# Generated by FakeRAM 2.0
VERSION 5.7 ;
BUSBITCHARS "[]" ;
PROPERTYDEFINITIONS
  MACRO width INTEGER ;
  MACRO depth INTEGER ;
  MACRO banks INTEGER ;
END PROPERTYDEFINITIONS
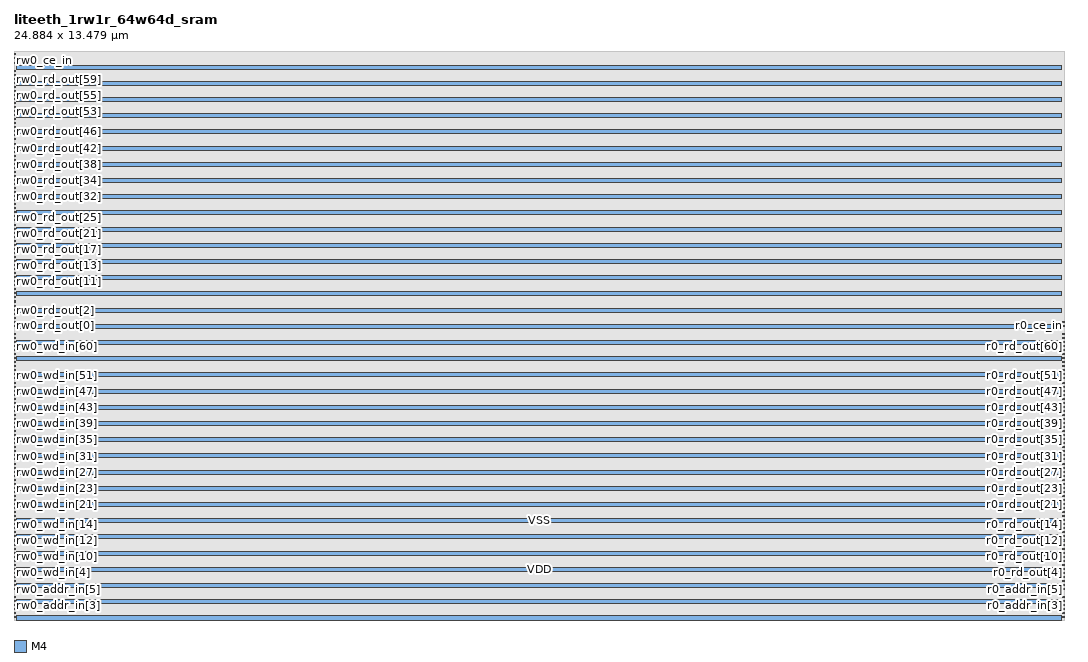
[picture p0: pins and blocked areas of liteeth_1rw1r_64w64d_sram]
MACRO liteeth_1rw1r_64w64d_sram
  PROPERTY width 64 ;
  PROPERTY depth 64 ;
  PROPERTY banks 1 ;
  FOREIGN liteeth_1rw1r_64w64d_sram 0 0 ;
  SYMMETRY X Y R90 ;
  SIZE 24.884 BY 13.479 ;
  CLASS BLOCK ;
  PIN r0_addr_in[0]
    DIRECTION INPUT ;
    USE SIGNAL ;
    SHAPE ABUTMENT ;
    PORT
      LAYER M4 ;
      RECT 24.860 0.048 24.884 0.072 ;
    END
  END r0_addr_in[0]
  PIN r0_addr_in[1]
    DIRECTION INPUT ;
    USE SIGNAL ;
    SHAPE ABUTMENT ;
    PORT
      LAYER M4 ;
      RECT 24.860 0.144 24.884 0.168 ;
    END
  END r0_addr_in[1]
  PIN r0_addr_in[2]
    DIRECTION INPUT ;
    USE SIGNAL ;
    SHAPE ABUTMENT ;
    PORT
      LAYER M4 ;
      RECT 24.860 0.240 24.884 0.264 ;
    END
  END r0_addr_in[2]
  PIN r0_addr_in[3]
    DIRECTION INPUT ;
    USE SIGNAL ;
    SHAPE ABUTMENT ;
    PORT
      LAYER M4 ;
      RECT 24.860 0.336 24.884 0.360 ;
    END
  END r0_addr_in[3]
  PIN r0_addr_in[4]
    DIRECTION INPUT ;
    USE SIGNAL ;
    SHAPE ABUTMENT ;
    PORT
      LAYER M4 ;
      RECT 24.860 0.432 24.884 0.456 ;
    END
  END r0_addr_in[4]
  PIN r0_addr_in[5]
    DIRECTION INPUT ;
    USE SIGNAL ;
    SHAPE ABUTMENT ;
    PORT
      LAYER M4 ;
      RECT 24.860 0.528 24.884 0.552 ;
    END
  END r0_addr_in[5]
  PIN r0_rd_out[0]
    DIRECTION OUTPUT ;
    USE SIGNAL ;
    SHAPE ABUTMENT ;
    PORT
      LAYER M4 ;
      RECT 24.860 0.720 24.884 0.744 ;
    END
  END r0_rd_out[0]
  PIN r0_rd_out[1]
    DIRECTION OUTPUT ;
    USE SIGNAL ;
    SHAPE ABUTMENT ;
    PORT
      LAYER M4 ;
      RECT 24.860 0.816 24.884 0.840 ;
    END
  END r0_rd_out[1]
  PIN r0_rd_out[2]
    DIRECTION OUTPUT ;
    USE SIGNAL ;
    SHAPE ABUTMENT ;
    PORT
      LAYER M4 ;
      RECT 24.860 0.912 24.884 0.936 ;
    END
  END r0_rd_out[2]
  PIN r0_rd_out[3]
    DIRECTION OUTPUT ;
    USE SIGNAL ;
    SHAPE ABUTMENT ;
    PORT
      LAYER M4 ;
      RECT 24.860 1.008 24.884 1.032 ;
    END
  END r0_rd_out[3]
  PIN r0_rd_out[4]
    DIRECTION OUTPUT ;
    USE SIGNAL ;
    SHAPE ABUTMENT ;
    PORT
      LAYER M4 ;
      RECT 24.860 1.104 24.884 1.128 ;
    END
  END r0_rd_out[4]
  PIN r0_rd_out[5]
    DIRECTION OUTPUT ;
    USE SIGNAL ;
    SHAPE ABUTMENT ;
    PORT
      LAYER M4 ;
      RECT 24.860 1.200 24.884 1.224 ;
    END
  END r0_rd_out[5]
  PIN r0_rd_out[6]
    DIRECTION OUTPUT ;
    USE SIGNAL ;
    SHAPE ABUTMENT ;
    PORT
      LAYER M4 ;
      RECT 24.860 1.296 24.884 1.320 ;
    END
  END r0_rd_out[6]
  PIN r0_rd_out[7]
    DIRECTION OUTPUT ;
    USE SIGNAL ;
    SHAPE ABUTMENT ;
    PORT
      LAYER M4 ;
      RECT 24.860 1.392 24.884 1.416 ;
    END
  END r0_rd_out[7]
  PIN r0_rd_out[8]
    DIRECTION OUTPUT ;
    USE SIGNAL ;
    SHAPE ABUTMENT ;
    PORT
      LAYER M4 ;
      RECT 24.860 1.488 24.884 1.512 ;
    END
  END r0_rd_out[8]
  PIN r0_rd_out[9]
    DIRECTION OUTPUT ;
    USE SIGNAL ;
    SHAPE ABUTMENT ;
    PORT
      LAYER M4 ;
      RECT 24.860 1.584 24.884 1.608 ;
    END
  END r0_rd_out[9]
  PIN r0_rd_out[10]
    DIRECTION OUTPUT ;
    USE SIGNAL ;
    SHAPE ABUTMENT ;
    PORT
      LAYER M4 ;
      RECT 24.860 1.680 24.884 1.704 ;
    END
  END r0_rd_out[10]
  PIN r0_rd_out[11]
    DIRECTION OUTPUT ;
    USE SIGNAL ;
    SHAPE ABUTMENT ;
    PORT
      LAYER M4 ;
      RECT 24.860 1.776 24.884 1.800 ;
    END
  END r0_rd_out[11]
  PIN r0_rd_out[12]
    DIRECTION OUTPUT ;
    USE SIGNAL ;
    SHAPE ABUTMENT ;
    PORT
      LAYER M4 ;
      RECT 24.860 1.872 24.884 1.896 ;
    END
  END r0_rd_out[12]
  PIN r0_rd_out[13]
    DIRECTION OUTPUT ;
    USE SIGNAL ;
    SHAPE ABUTMENT ;
    PORT
      LAYER M4 ;
      RECT 24.860 1.968 24.884 1.992 ;
    END
  END r0_rd_out[13]
  PIN r0_rd_out[14]
    DIRECTION OUTPUT ;
    USE SIGNAL ;
    SHAPE ABUTMENT ;
    PORT
      LAYER M4 ;
      RECT 24.860 2.064 24.884 2.088 ;
    END
  END r0_rd_out[14]
  PIN r0_rd_out[15]
    DIRECTION OUTPUT ;
    USE SIGNAL ;
    SHAPE ABUTMENT ;
    PORT
      LAYER M4 ;
      RECT 24.860 2.160 24.884 2.184 ;
    END
  END r0_rd_out[15]
  PIN r0_rd_out[16]
    DIRECTION OUTPUT ;
    USE SIGNAL ;
    SHAPE ABUTMENT ;
    PORT
      LAYER M4 ;
      RECT 24.860 2.256 24.884 2.280 ;
    END
  END r0_rd_out[16]
  PIN r0_rd_out[17]
    DIRECTION OUTPUT ;
    USE SIGNAL ;
    SHAPE ABUTMENT ;
    PORT
      LAYER M4 ;
      RECT 24.860 2.352 24.884 2.376 ;
    END
  END r0_rd_out[17]
  PIN r0_rd_out[18]
    DIRECTION OUTPUT ;
    USE SIGNAL ;
    SHAPE ABUTMENT ;
    PORT
      LAYER M4 ;
      RECT 24.860 2.448 24.884 2.472 ;
    END
  END r0_rd_out[18]
  PIN r0_rd_out[19]
    DIRECTION OUTPUT ;
    USE SIGNAL ;
    SHAPE ABUTMENT ;
    PORT
      LAYER M4 ;
      RECT 24.860 2.544 24.884 2.568 ;
    END
  END r0_rd_out[19]
  PIN r0_rd_out[20]
    DIRECTION OUTPUT ;
    USE SIGNAL ;
    SHAPE ABUTMENT ;
    PORT
      LAYER M4 ;
      RECT 24.860 2.640 24.884 2.664 ;
    END
  END r0_rd_out[20]
  PIN r0_rd_out[21]
    DIRECTION OUTPUT ;
    USE SIGNAL ;
    SHAPE ABUTMENT ;
    PORT
      LAYER M4 ;
      RECT 24.860 2.736 24.884 2.760 ;
    END
  END r0_rd_out[21]
  PIN r0_rd_out[22]
    DIRECTION OUTPUT ;
    USE SIGNAL ;
    SHAPE ABUTMENT ;
    PORT
      LAYER M4 ;
      RECT 24.860 2.832 24.884 2.856 ;
    END
  END r0_rd_out[22]
  PIN r0_rd_out[23]
    DIRECTION OUTPUT ;
    USE SIGNAL ;
    SHAPE ABUTMENT ;
    PORT
      LAYER M4 ;
      RECT 24.860 2.928 24.884 2.952 ;
    END
  END r0_rd_out[23]
  PIN r0_rd_out[24]
    DIRECTION OUTPUT ;
    USE SIGNAL ;
    SHAPE ABUTMENT ;
    PORT
      LAYER M4 ;
      RECT 24.860 3.024 24.884 3.048 ;
    END
  END r0_rd_out[24]
  PIN r0_rd_out[25]
    DIRECTION OUTPUT ;
    USE SIGNAL ;
    SHAPE ABUTMENT ;
    PORT
      LAYER M4 ;
      RECT 24.860 3.120 24.884 3.144 ;
    END
  END r0_rd_out[25]
  PIN r0_rd_out[26]
    DIRECTION OUTPUT ;
    USE SIGNAL ;
    SHAPE ABUTMENT ;
    PORT
      LAYER M4 ;
      RECT 24.860 3.216 24.884 3.240 ;
    END
  END r0_rd_out[26]
  PIN r0_rd_out[27]
    DIRECTION OUTPUT ;
    USE SIGNAL ;
    SHAPE ABUTMENT ;
    PORT
      LAYER M4 ;
      RECT 24.860 3.312 24.884 3.336 ;
    END
  END r0_rd_out[27]
  PIN r0_rd_out[28]
    DIRECTION OUTPUT ;
    USE SIGNAL ;
    SHAPE ABUTMENT ;
    PORT
      LAYER M4 ;
      RECT 24.860 3.408 24.884 3.432 ;
    END
  END r0_rd_out[28]
  PIN r0_rd_out[29]
    DIRECTION OUTPUT ;
    USE SIGNAL ;
    SHAPE ABUTMENT ;
    PORT
      LAYER M4 ;
      RECT 24.860 3.504 24.884 3.528 ;
    END
  END r0_rd_out[29]
  PIN r0_rd_out[30]
    DIRECTION OUTPUT ;
    USE SIGNAL ;
    SHAPE ABUTMENT ;
    PORT
      LAYER M4 ;
      RECT 24.860 3.600 24.884 3.624 ;
    END
  END r0_rd_out[30]
  PIN r0_rd_out[31]
    DIRECTION OUTPUT ;
    USE SIGNAL ;
    SHAPE ABUTMENT ;
    PORT
      LAYER M4 ;
      RECT 24.860 3.696 24.884 3.720 ;
    END
  END r0_rd_out[31]
  PIN r0_rd_out[32]
    DIRECTION OUTPUT ;
    USE SIGNAL ;
    SHAPE ABUTMENT ;
    PORT
      LAYER M4 ;
      RECT 24.860 3.792 24.884 3.816 ;
    END
  END r0_rd_out[32]
  PIN r0_rd_out[33]
    DIRECTION OUTPUT ;
    USE SIGNAL ;
    SHAPE ABUTMENT ;
    PORT
      LAYER M4 ;
      RECT 24.860 3.888 24.884 3.912 ;
    END
  END r0_rd_out[33]
  PIN r0_rd_out[34]
    DIRECTION OUTPUT ;
    USE SIGNAL ;
    SHAPE ABUTMENT ;
    PORT
      LAYER M4 ;
      RECT 24.860 3.984 24.884 4.008 ;
    END
  END r0_rd_out[34]
  PIN r0_rd_out[35]
    DIRECTION OUTPUT ;
    USE SIGNAL ;
    SHAPE ABUTMENT ;
    PORT
      LAYER M4 ;
      RECT 24.860 4.080 24.884 4.104 ;
    END
  END r0_rd_out[35]
  PIN r0_rd_out[36]
    DIRECTION OUTPUT ;
    USE SIGNAL ;
    SHAPE ABUTMENT ;
    PORT
      LAYER M4 ;
      RECT 24.860 4.176 24.884 4.200 ;
    END
  END r0_rd_out[36]
  PIN r0_rd_out[37]
    DIRECTION OUTPUT ;
    USE SIGNAL ;
    SHAPE ABUTMENT ;
    PORT
      LAYER M4 ;
      RECT 24.860 4.272 24.884 4.296 ;
    END
  END r0_rd_out[37]
  PIN r0_rd_out[38]
    DIRECTION OUTPUT ;
    USE SIGNAL ;
    SHAPE ABUTMENT ;
    PORT
      LAYER M4 ;
      RECT 24.860 4.368 24.884 4.392 ;
    END
  END r0_rd_out[38]
  PIN r0_rd_out[39]
    DIRECTION OUTPUT ;
    USE SIGNAL ;
    SHAPE ABUTMENT ;
    PORT
      LAYER M4 ;
      RECT 24.860 4.464 24.884 4.488 ;
    END
  END r0_rd_out[39]
  PIN r0_rd_out[40]
    DIRECTION OUTPUT ;
    USE SIGNAL ;
    SHAPE ABUTMENT ;
    PORT
      LAYER M4 ;
      RECT 24.860 4.560 24.884 4.584 ;
    END
  END r0_rd_out[40]
  PIN r0_rd_out[41]
    DIRECTION OUTPUT ;
    USE SIGNAL ;
    SHAPE ABUTMENT ;
    PORT
      LAYER M4 ;
      RECT 24.860 4.656 24.884 4.680 ;
    END
  END r0_rd_out[41]
  PIN r0_rd_out[42]
    DIRECTION OUTPUT ;
    USE SIGNAL ;
    SHAPE ABUTMENT ;
    PORT
      LAYER M4 ;
      RECT 24.860 4.752 24.884 4.776 ;
    END
  END r0_rd_out[42]
  PIN r0_rd_out[43]
    DIRECTION OUTPUT ;
    USE SIGNAL ;
    SHAPE ABUTMENT ;
    PORT
      LAYER M4 ;
      RECT 24.860 4.848 24.884 4.872 ;
    END
  END r0_rd_out[43]
  PIN r0_rd_out[44]
    DIRECTION OUTPUT ;
    USE SIGNAL ;
    SHAPE ABUTMENT ;
    PORT
      LAYER M4 ;
      RECT 24.860 4.944 24.884 4.968 ;
    END
  END r0_rd_out[44]
  PIN r0_rd_out[45]
    DIRECTION OUTPUT ;
    USE SIGNAL ;
    SHAPE ABUTMENT ;
    PORT
      LAYER M4 ;
      RECT 24.860 5.040 24.884 5.064 ;
    END
  END r0_rd_out[45]
  PIN r0_rd_out[46]
    DIRECTION OUTPUT ;
    USE SIGNAL ;
    SHAPE ABUTMENT ;
    PORT
      LAYER M4 ;
      RECT 24.860 5.136 24.884 5.160 ;
    END
  END r0_rd_out[46]
  PIN r0_rd_out[47]
    DIRECTION OUTPUT ;
    USE SIGNAL ;
    SHAPE ABUTMENT ;
    PORT
      LAYER M4 ;
      RECT 24.860 5.232 24.884 5.256 ;
    END
  END r0_rd_out[47]
  PIN r0_rd_out[48]
    DIRECTION OUTPUT ;
    USE SIGNAL ;
    SHAPE ABUTMENT ;
    PORT
      LAYER M4 ;
      RECT 24.860 5.328 24.884 5.352 ;
    END
  END r0_rd_out[48]
  PIN r0_rd_out[49]
    DIRECTION OUTPUT ;
    USE SIGNAL ;
    SHAPE ABUTMENT ;
    PORT
      LAYER M4 ;
      RECT 24.860 5.424 24.884 5.448 ;
    END
  END r0_rd_out[49]
  PIN r0_rd_out[50]
    DIRECTION OUTPUT ;
    USE SIGNAL ;
    SHAPE ABUTMENT ;
    PORT
      LAYER M4 ;
      RECT 24.860 5.520 24.884 5.544 ;
    END
  END r0_rd_out[50]
  PIN r0_rd_out[51]
    DIRECTION OUTPUT ;
    USE SIGNAL ;
    SHAPE ABUTMENT ;
    PORT
      LAYER M4 ;
      RECT 24.860 5.616 24.884 5.640 ;
    END
  END r0_rd_out[51]
  PIN r0_rd_out[52]
    DIRECTION OUTPUT ;
    USE SIGNAL ;
    SHAPE ABUTMENT ;
    PORT
      LAYER M4 ;
      RECT 24.860 5.712 24.884 5.736 ;
    END
  END r0_rd_out[52]
  PIN r0_rd_out[53]
    DIRECTION OUTPUT ;
    USE SIGNAL ;
    SHAPE ABUTMENT ;
    PORT
      LAYER M4 ;
      RECT 24.860 5.808 24.884 5.832 ;
    END
  END r0_rd_out[53]
  PIN r0_rd_out[54]
    DIRECTION OUTPUT ;
    USE SIGNAL ;
    SHAPE ABUTMENT ;
    PORT
      LAYER M4 ;
      RECT 24.860 5.904 24.884 5.928 ;
    END
  END r0_rd_out[54]
  PIN r0_rd_out[55]
    DIRECTION OUTPUT ;
    USE SIGNAL ;
    SHAPE ABUTMENT ;
    PORT
      LAYER M4 ;
      RECT 24.860 6.000 24.884 6.024 ;
    END
  END r0_rd_out[55]
  PIN r0_rd_out[56]
    DIRECTION OUTPUT ;
    USE SIGNAL ;
    SHAPE ABUTMENT ;
    PORT
      LAYER M4 ;
      RECT 24.860 6.096 24.884 6.120 ;
    END
  END r0_rd_out[56]
  PIN r0_rd_out[57]
    DIRECTION OUTPUT ;
    USE SIGNAL ;
    SHAPE ABUTMENT ;
    PORT
      LAYER M4 ;
      RECT 24.860 6.192 24.884 6.216 ;
    END
  END r0_rd_out[57]
  PIN r0_rd_out[58]
    DIRECTION OUTPUT ;
    USE SIGNAL ;
    SHAPE ABUTMENT ;
    PORT
      LAYER M4 ;
      RECT 24.860 6.288 24.884 6.312 ;
    END
  END r0_rd_out[58]
  PIN r0_rd_out[59]
    DIRECTION OUTPUT ;
    USE SIGNAL ;
    SHAPE ABUTMENT ;
    PORT
      LAYER M4 ;
      RECT 24.860 6.384 24.884 6.408 ;
    END
  END r0_rd_out[59]
  PIN r0_rd_out[60]
    DIRECTION OUTPUT ;
    USE SIGNAL ;
    SHAPE ABUTMENT ;
    PORT
      LAYER M4 ;
      RECT 24.860 6.480 24.884 6.504 ;
    END
  END r0_rd_out[60]
  PIN r0_rd_out[61]
    DIRECTION OUTPUT ;
    USE SIGNAL ;
    SHAPE ABUTMENT ;
    PORT
      LAYER M4 ;
      RECT 24.860 6.576 24.884 6.600 ;
    END
  END r0_rd_out[61]
  PIN r0_rd_out[62]
    DIRECTION OUTPUT ;
    USE SIGNAL ;
    SHAPE ABUTMENT ;
    PORT
      LAYER M4 ;
      RECT 24.860 6.672 24.884 6.696 ;
    END
  END r0_rd_out[62]
  PIN r0_rd_out[63]
    DIRECTION OUTPUT ;
    USE SIGNAL ;
    SHAPE ABUTMENT ;
    PORT
      LAYER M4 ;
      RECT 24.860 6.768 24.884 6.792 ;
    END
  END r0_rd_out[63]
  PIN r0_ce_in
    DIRECTION INPUT ;
    USE SIGNAL ;
    SHAPE ABUTMENT ;
    PORT
      LAYER M4 ;
      RECT 24.860 6.960 24.884 6.984 ;
    END
  END r0_ce_in
  PIN r0_clk
    DIRECTION INPUT ;
    USE SIGNAL ;
    SHAPE ABUTMENT ;
    PORT
      LAYER M4 ;
      RECT 24.860 7.056 24.884 7.080 ;
    END
  END r0_clk
  PIN rw0_addr_in[0]
    DIRECTION INPUT ;
    USE SIGNAL ;
    SHAPE ABUTMENT ;
    PORT
      LAYER M4 ;
      RECT 0.000 0.048 0.024 0.072 ;
    END
  END rw0_addr_in[0]
  PIN rw0_addr_in[1]
    DIRECTION INPUT ;
    USE SIGNAL ;
    SHAPE ABUTMENT ;
    PORT
      LAYER M4 ;
      RECT 0.000 0.144 0.024 0.168 ;
    END
  END rw0_addr_in[1]
  PIN rw0_addr_in[2]
    DIRECTION INPUT ;
    USE SIGNAL ;
    SHAPE ABUTMENT ;
    PORT
      LAYER M4 ;
      RECT 0.000 0.240 0.024 0.264 ;
    END
  END rw0_addr_in[2]
  PIN rw0_addr_in[3]
    DIRECTION INPUT ;
    USE SIGNAL ;
    SHAPE ABUTMENT ;
    PORT
      LAYER M4 ;
      RECT 0.000 0.336 0.024 0.360 ;
    END
  END rw0_addr_in[3]
  PIN rw0_addr_in[4]
    DIRECTION INPUT ;
    USE SIGNAL ;
    SHAPE ABUTMENT ;
    PORT
      LAYER M4 ;
      RECT 0.000 0.432 0.024 0.456 ;
    END
  END rw0_addr_in[4]
  PIN rw0_addr_in[5]
    DIRECTION INPUT ;
    USE SIGNAL ;
    SHAPE ABUTMENT ;
    PORT
      LAYER M4 ;
      RECT 0.000 0.528 0.024 0.552 ;
    END
  END rw0_addr_in[5]
  PIN rw0_wd_in[0]
    DIRECTION INPUT ;
    USE SIGNAL ;
    SHAPE ABUTMENT ;
    PORT
      LAYER M4 ;
      RECT 0.000 0.720 0.024 0.744 ;
    END
  END rw0_wd_in[0]
  PIN rw0_wd_in[1]
    DIRECTION INPUT ;
    USE SIGNAL ;
    SHAPE ABUTMENT ;
    PORT
      LAYER M4 ;
      RECT 0.000 0.816 0.024 0.840 ;
    END
  END rw0_wd_in[1]
  PIN rw0_wd_in[2]
    DIRECTION INPUT ;
    USE SIGNAL ;
    SHAPE ABUTMENT ;
    PORT
      LAYER M4 ;
      RECT 0.000 0.912 0.024 0.936 ;
    END
  END rw0_wd_in[2]
  PIN rw0_wd_in[3]
    DIRECTION INPUT ;
    USE SIGNAL ;
    SHAPE ABUTMENT ;
    PORT
      LAYER M4 ;
      RECT 0.000 1.008 0.024 1.032 ;
    END
  END rw0_wd_in[3]
  PIN rw0_wd_in[4]
    DIRECTION INPUT ;
    USE SIGNAL ;
    SHAPE ABUTMENT ;
    PORT
      LAYER M4 ;
      RECT 0.000 1.104 0.024 1.128 ;
    END
  END rw0_wd_in[4]
  PIN rw0_wd_in[5]
    DIRECTION INPUT ;
    USE SIGNAL ;
    SHAPE ABUTMENT ;
    PORT
      LAYER M4 ;
      RECT 0.000 1.200 0.024 1.224 ;
    END
  END rw0_wd_in[5]
  PIN rw0_wd_in[6]
    DIRECTION INPUT ;
    USE SIGNAL ;
    SHAPE ABUTMENT ;
    PORT
      LAYER M4 ;
      RECT 0.000 1.296 0.024 1.320 ;
    END
  END rw0_wd_in[6]
  PIN rw0_wd_in[7]
    DIRECTION INPUT ;
    USE SIGNAL ;
    SHAPE ABUTMENT ;
    PORT
      LAYER M4 ;
      RECT 0.000 1.392 0.024 1.416 ;
    END
  END rw0_wd_in[7]
  PIN rw0_wd_in[8]
    DIRECTION INPUT ;
    USE SIGNAL ;
    SHAPE ABUTMENT ;
    PORT
      LAYER M4 ;
      RECT 0.000 1.488 0.024 1.512 ;
    END
  END rw0_wd_in[8]
  PIN rw0_wd_in[9]
    DIRECTION INPUT ;
    USE SIGNAL ;
    SHAPE ABUTMENT ;
    PORT
      LAYER M4 ;
      RECT 0.000 1.584 0.024 1.608 ;
    END
  END rw0_wd_in[9]
  PIN rw0_wd_in[10]
    DIRECTION INPUT ;
    USE SIGNAL ;
    SHAPE ABUTMENT ;
    PORT
      LAYER M4 ;
      RECT 0.000 1.680 0.024 1.704 ;
    END
  END rw0_wd_in[10]
  PIN rw0_wd_in[11]
    DIRECTION INPUT ;
    USE SIGNAL ;
    SHAPE ABUTMENT ;
    PORT
      LAYER M4 ;
      RECT 0.000 1.776 0.024 1.800 ;
    END
  END rw0_wd_in[11]
  PIN rw0_wd_in[12]
    DIRECTION INPUT ;
    USE SIGNAL ;
    SHAPE ABUTMENT ;
    PORT
      LAYER M4 ;
      RECT 0.000 1.872 0.024 1.896 ;
    END
  END rw0_wd_in[12]
  PIN rw0_wd_in[13]
    DIRECTION INPUT ;
    USE SIGNAL ;
    SHAPE ABUTMENT ;
    PORT
      LAYER M4 ;
      RECT 0.000 1.968 0.024 1.992 ;
    END
  END rw0_wd_in[13]
  PIN rw0_wd_in[14]
    DIRECTION INPUT ;
    USE SIGNAL ;
    SHAPE ABUTMENT ;
    PORT
      LAYER M4 ;
      RECT 0.000 2.064 0.024 2.088 ;
    END
  END rw0_wd_in[14]
  PIN rw0_wd_in[15]
    DIRECTION INPUT ;
    USE SIGNAL ;
    SHAPE ABUTMENT ;
    PORT
      LAYER M4 ;
      RECT 0.000 2.160 0.024 2.184 ;
    END
  END rw0_wd_in[15]
  PIN rw0_wd_in[16]
    DIRECTION INPUT ;
    USE SIGNAL ;
    SHAPE ABUTMENT ;
    PORT
      LAYER M4 ;
      RECT 0.000 2.256 0.024 2.280 ;
    END
  END rw0_wd_in[16]
  PIN rw0_wd_in[17]
    DIRECTION INPUT ;
    USE SIGNAL ;
    SHAPE ABUTMENT ;
    PORT
      LAYER M4 ;
      RECT 0.000 2.352 0.024 2.376 ;
    END
  END rw0_wd_in[17]
  PIN rw0_wd_in[18]
    DIRECTION INPUT ;
    USE SIGNAL ;
    SHAPE ABUTMENT ;
    PORT
      LAYER M4 ;
      RECT 0.000 2.448 0.024 2.472 ;
    END
  END rw0_wd_in[18]
  PIN rw0_wd_in[19]
    DIRECTION INPUT ;
    USE SIGNAL ;
    SHAPE ABUTMENT ;
    PORT
      LAYER M4 ;
      RECT 0.000 2.544 0.024 2.568 ;
    END
  END rw0_wd_in[19]
  PIN rw0_wd_in[20]
    DIRECTION INPUT ;
    USE SIGNAL ;
    SHAPE ABUTMENT ;
    PORT
      LAYER M4 ;
      RECT 0.000 2.640 0.024 2.664 ;
    END
  END rw0_wd_in[20]
  PIN rw0_wd_in[21]
    DIRECTION INPUT ;
    USE SIGNAL ;
    SHAPE ABUTMENT ;
    PORT
      LAYER M4 ;
      RECT 0.000 2.736 0.024 2.760 ;
    END
  END rw0_wd_in[21]
  PIN rw0_wd_in[22]
    DIRECTION INPUT ;
    USE SIGNAL ;
    SHAPE ABUTMENT ;
    PORT
      LAYER M4 ;
      RECT 0.000 2.832 0.024 2.856 ;
    END
  END rw0_wd_in[22]
  PIN rw0_wd_in[23]
    DIRECTION INPUT ;
    USE SIGNAL ;
    SHAPE ABUTMENT ;
    PORT
      LAYER M4 ;
      RECT 0.000 2.928 0.024 2.952 ;
    END
  END rw0_wd_in[23]
  PIN rw0_wd_in[24]
    DIRECTION INPUT ;
    USE SIGNAL ;
    SHAPE ABUTMENT ;
    PORT
      LAYER M4 ;
      RECT 0.000 3.024 0.024 3.048 ;
    END
  END rw0_wd_in[24]
  PIN rw0_wd_in[25]
    DIRECTION INPUT ;
    USE SIGNAL ;
    SHAPE ABUTMENT ;
    PORT
      LAYER M4 ;
      RECT 0.000 3.120 0.024 3.144 ;
    END
  END rw0_wd_in[25]
  PIN rw0_wd_in[26]
    DIRECTION INPUT ;
    USE SIGNAL ;
    SHAPE ABUTMENT ;
    PORT
      LAYER M4 ;
      RECT 0.000 3.216 0.024 3.240 ;
    END
  END rw0_wd_in[26]
  PIN rw0_wd_in[27]
    DIRECTION INPUT ;
    USE SIGNAL ;
    SHAPE ABUTMENT ;
    PORT
      LAYER M4 ;
      RECT 0.000 3.312 0.024 3.336 ;
    END
  END rw0_wd_in[27]
  PIN rw0_wd_in[28]
    DIRECTION INPUT ;
    USE SIGNAL ;
    SHAPE ABUTMENT ;
    PORT
      LAYER M4 ;
      RECT 0.000 3.408 0.024 3.432 ;
    END
  END rw0_wd_in[28]
  PIN rw0_wd_in[29]
    DIRECTION INPUT ;
    USE SIGNAL ;
    SHAPE ABUTMENT ;
    PORT
      LAYER M4 ;
      RECT 0.000 3.504 0.024 3.528 ;
    END
  END rw0_wd_in[29]
  PIN rw0_wd_in[30]
    DIRECTION INPUT ;
    USE SIGNAL ;
    SHAPE ABUTMENT ;
    PORT
      LAYER M4 ;
      RECT 0.000 3.600 0.024 3.624 ;
    END
  END rw0_wd_in[30]
  PIN rw0_wd_in[31]
    DIRECTION INPUT ;
    USE SIGNAL ;
    SHAPE ABUTMENT ;
    PORT
      LAYER M4 ;
      RECT 0.000 3.696 0.024 3.720 ;
    END
  END rw0_wd_in[31]
  PIN rw0_wd_in[32]
    DIRECTION INPUT ;
    USE SIGNAL ;
    SHAPE ABUTMENT ;
    PORT
      LAYER M4 ;
      RECT 0.000 3.792 0.024 3.816 ;
    END
  END rw0_wd_in[32]
  PIN rw0_wd_in[33]
    DIRECTION INPUT ;
    USE SIGNAL ;
    SHAPE ABUTMENT ;
    PORT
      LAYER M4 ;
      RECT 0.000 3.888 0.024 3.912 ;
    END
  END rw0_wd_in[33]
  PIN rw0_wd_in[34]
    DIRECTION INPUT ;
    USE SIGNAL ;
    SHAPE ABUTMENT ;
    PORT
      LAYER M4 ;
      RECT 0.000 3.984 0.024 4.008 ;
    END
  END rw0_wd_in[34]
  PIN rw0_wd_in[35]
    DIRECTION INPUT ;
    USE SIGNAL ;
    SHAPE ABUTMENT ;
    PORT
      LAYER M4 ;
      RECT 0.000 4.080 0.024 4.104 ;
    END
  END rw0_wd_in[35]
  PIN rw0_wd_in[36]
    DIRECTION INPUT ;
    USE SIGNAL ;
    SHAPE ABUTMENT ;
    PORT
      LAYER M4 ;
      RECT 0.000 4.176 0.024 4.200 ;
    END
  END rw0_wd_in[36]
  PIN rw0_wd_in[37]
    DIRECTION INPUT ;
    USE SIGNAL ;
    SHAPE ABUTMENT ;
    PORT
      LAYER M4 ;
      RECT 0.000 4.272 0.024 4.296 ;
    END
  END rw0_wd_in[37]
  PIN rw0_wd_in[38]
    DIRECTION INPUT ;
    USE SIGNAL ;
    SHAPE ABUTMENT ;
    PORT
      LAYER M4 ;
      RECT 0.000 4.368 0.024 4.392 ;
    END
  END rw0_wd_in[38]
  PIN rw0_wd_in[39]
    DIRECTION INPUT ;
    USE SIGNAL ;
    SHAPE ABUTMENT ;
    PORT
      LAYER M4 ;
      RECT 0.000 4.464 0.024 4.488 ;
    END
  END rw0_wd_in[39]
  PIN rw0_wd_in[40]
    DIRECTION INPUT ;
    USE SIGNAL ;
    SHAPE ABUTMENT ;
    PORT
      LAYER M4 ;
      RECT 0.000 4.560 0.024 4.584 ;
    END
  END rw0_wd_in[40]
  PIN rw0_wd_in[41]
    DIRECTION INPUT ;
    USE SIGNAL ;
    SHAPE ABUTMENT ;
    PORT
      LAYER M4 ;
      RECT 0.000 4.656 0.024 4.680 ;
    END
  END rw0_wd_in[41]
  PIN rw0_wd_in[42]
    DIRECTION INPUT ;
    USE SIGNAL ;
    SHAPE ABUTMENT ;
    PORT
      LAYER M4 ;
      RECT 0.000 4.752 0.024 4.776 ;
    END
  END rw0_wd_in[42]
  PIN rw0_wd_in[43]
    DIRECTION INPUT ;
    USE SIGNAL ;
    SHAPE ABUTMENT ;
    PORT
      LAYER M4 ;
      RECT 0.000 4.848 0.024 4.872 ;
    END
  END rw0_wd_in[43]
  PIN rw0_wd_in[44]
    DIRECTION INPUT ;
    USE SIGNAL ;
    SHAPE ABUTMENT ;
    PORT
      LAYER M4 ;
      RECT 0.000 4.944 0.024 4.968 ;
    END
  END rw0_wd_in[44]
  PIN rw0_wd_in[45]
    DIRECTION INPUT ;
    USE SIGNAL ;
    SHAPE ABUTMENT ;
    PORT
      LAYER M4 ;
      RECT 0.000 5.040 0.024 5.064 ;
    END
  END rw0_wd_in[45]
  PIN rw0_wd_in[46]
    DIRECTION INPUT ;
    USE SIGNAL ;
    SHAPE ABUTMENT ;
    PORT
      LAYER M4 ;
      RECT 0.000 5.136 0.024 5.160 ;
    END
  END rw0_wd_in[46]
  PIN rw0_wd_in[47]
    DIRECTION INPUT ;
    USE SIGNAL ;
    SHAPE ABUTMENT ;
    PORT
      LAYER M4 ;
      RECT 0.000 5.232 0.024 5.256 ;
    END
  END rw0_wd_in[47]
  PIN rw0_wd_in[48]
    DIRECTION INPUT ;
    USE SIGNAL ;
    SHAPE ABUTMENT ;
    PORT
      LAYER M4 ;
      RECT 0.000 5.328 0.024 5.352 ;
    END
  END rw0_wd_in[48]
  PIN rw0_wd_in[49]
    DIRECTION INPUT ;
    USE SIGNAL ;
    SHAPE ABUTMENT ;
    PORT
      LAYER M4 ;
      RECT 0.000 5.424 0.024 5.448 ;
    END
  END rw0_wd_in[49]
  PIN rw0_wd_in[50]
    DIRECTION INPUT ;
    USE SIGNAL ;
    SHAPE ABUTMENT ;
    PORT
      LAYER M4 ;
      RECT 0.000 5.520 0.024 5.544 ;
    END
  END rw0_wd_in[50]
  PIN rw0_wd_in[51]
    DIRECTION INPUT ;
    USE SIGNAL ;
    SHAPE ABUTMENT ;
    PORT
      LAYER M4 ;
      RECT 0.000 5.616 0.024 5.640 ;
    END
  END rw0_wd_in[51]
  PIN rw0_wd_in[52]
    DIRECTION INPUT ;
    USE SIGNAL ;
    SHAPE ABUTMENT ;
    PORT
      LAYER M4 ;
      RECT 0.000 5.712 0.024 5.736 ;
    END
  END rw0_wd_in[52]
  PIN rw0_wd_in[53]
    DIRECTION INPUT ;
    USE SIGNAL ;
    SHAPE ABUTMENT ;
    PORT
      LAYER M4 ;
      RECT 0.000 5.808 0.024 5.832 ;
    END
  END rw0_wd_in[53]
  PIN rw0_wd_in[54]
    DIRECTION INPUT ;
    USE SIGNAL ;
    SHAPE ABUTMENT ;
    PORT
      LAYER M4 ;
      RECT 0.000 5.904 0.024 5.928 ;
    END
  END rw0_wd_in[54]
  PIN rw0_wd_in[55]
    DIRECTION INPUT ;
    USE SIGNAL ;
    SHAPE ABUTMENT ;
    PORT
      LAYER M4 ;
      RECT 0.000 6.000 0.024 6.024 ;
    END
  END rw0_wd_in[55]
  PIN rw0_wd_in[56]
    DIRECTION INPUT ;
    USE SIGNAL ;
    SHAPE ABUTMENT ;
    PORT
      LAYER M4 ;
      RECT 0.000 6.096 0.024 6.120 ;
    END
  END rw0_wd_in[56]
  PIN rw0_wd_in[57]
    DIRECTION INPUT ;
    USE SIGNAL ;
    SHAPE ABUTMENT ;
    PORT
      LAYER M4 ;
      RECT 0.000 6.192 0.024 6.216 ;
    END
  END rw0_wd_in[57]
  PIN rw0_wd_in[58]
    DIRECTION INPUT ;
    USE SIGNAL ;
    SHAPE ABUTMENT ;
    PORT
      LAYER M4 ;
      RECT 0.000 6.288 0.024 6.312 ;
    END
  END rw0_wd_in[58]
  PIN rw0_wd_in[59]
    DIRECTION INPUT ;
    USE SIGNAL ;
    SHAPE ABUTMENT ;
    PORT
      LAYER M4 ;
      RECT 0.000 6.384 0.024 6.408 ;
    END
  END rw0_wd_in[59]
  PIN rw0_wd_in[60]
    DIRECTION INPUT ;
    USE SIGNAL ;
    SHAPE ABUTMENT ;
    PORT
      LAYER M4 ;
      RECT 0.000 6.480 0.024 6.504 ;
    END
  END rw0_wd_in[60]
  PIN rw0_wd_in[61]
    DIRECTION INPUT ;
    USE SIGNAL ;
    SHAPE ABUTMENT ;
    PORT
      LAYER M4 ;
      RECT 0.000 6.576 0.024 6.600 ;
    END
  END rw0_wd_in[61]
  PIN rw0_wd_in[62]
    DIRECTION INPUT ;
    USE SIGNAL ;
    SHAPE ABUTMENT ;
    PORT
      LAYER M4 ;
      RECT 0.000 6.672 0.024 6.696 ;
    END
  END rw0_wd_in[62]
  PIN rw0_wd_in[63]
    DIRECTION INPUT ;
    USE SIGNAL ;
    SHAPE ABUTMENT ;
    PORT
      LAYER M4 ;
      RECT 0.000 6.768 0.024 6.792 ;
    END
  END rw0_wd_in[63]
  PIN rw0_rd_out[0]
    DIRECTION OUTPUT ;
    USE SIGNAL ;
    SHAPE ABUTMENT ;
    PORT
      LAYER M4 ;
      RECT 0.000 6.960 0.024 6.984 ;
    END
  END rw0_rd_out[0]
  PIN rw0_rd_out[1]
    DIRECTION OUTPUT ;
    USE SIGNAL ;
    SHAPE ABUTMENT ;
    PORT
      LAYER M4 ;
      RECT 0.000 7.056 0.024 7.080 ;
    END
  END rw0_rd_out[1]
  PIN rw0_rd_out[2]
    DIRECTION OUTPUT ;
    USE SIGNAL ;
    SHAPE ABUTMENT ;
    PORT
      LAYER M4 ;
      RECT 0.000 7.152 0.024 7.176 ;
    END
  END rw0_rd_out[2]
  PIN rw0_rd_out[3]
    DIRECTION OUTPUT ;
    USE SIGNAL ;
    SHAPE ABUTMENT ;
    PORT
      LAYER M4 ;
      RECT 0.000 7.248 0.024 7.272 ;
    END
  END rw0_rd_out[3]
  PIN rw0_rd_out[4]
    DIRECTION OUTPUT ;
    USE SIGNAL ;
    SHAPE ABUTMENT ;
    PORT
      LAYER M4 ;
      RECT 0.000 7.344 0.024 7.368 ;
    END
  END rw0_rd_out[4]
  PIN rw0_rd_out[5]
    DIRECTION OUTPUT ;
    USE SIGNAL ;
    SHAPE ABUTMENT ;
    PORT
      LAYER M4 ;
      RECT 0.000 7.440 0.024 7.464 ;
    END
  END rw0_rd_out[5]
  PIN rw0_rd_out[6]
    DIRECTION OUTPUT ;
    USE SIGNAL ;
    SHAPE ABUTMENT ;
    PORT
      LAYER M4 ;
      RECT 0.000 7.536 0.024 7.560 ;
    END
  END rw0_rd_out[6]
  PIN rw0_rd_out[7]
    DIRECTION OUTPUT ;
    USE SIGNAL ;
    SHAPE ABUTMENT ;
    PORT
      LAYER M4 ;
      RECT 0.000 7.632 0.024 7.656 ;
    END
  END rw0_rd_out[7]
  PIN rw0_rd_out[8]
    DIRECTION OUTPUT ;
    USE SIGNAL ;
    SHAPE ABUTMENT ;
    PORT
      LAYER M4 ;
      RECT 0.000 7.728 0.024 7.752 ;
    END
  END rw0_rd_out[8]
  PIN rw0_rd_out[9]
    DIRECTION OUTPUT ;
    USE SIGNAL ;
    SHAPE ABUTMENT ;
    PORT
      LAYER M4 ;
      RECT 0.000 7.824 0.024 7.848 ;
    END
  END rw0_rd_out[9]
  PIN rw0_rd_out[10]
    DIRECTION OUTPUT ;
    USE SIGNAL ;
    SHAPE ABUTMENT ;
    PORT
      LAYER M4 ;
      RECT 0.000 7.920 0.024 7.944 ;
    END
  END rw0_rd_out[10]
  PIN rw0_rd_out[11]
    DIRECTION OUTPUT ;
    USE SIGNAL ;
    SHAPE ABUTMENT ;
    PORT
      LAYER M4 ;
      RECT 0.000 8.016 0.024 8.040 ;
    END
  END rw0_rd_out[11]
  PIN rw0_rd_out[12]
    DIRECTION OUTPUT ;
    USE SIGNAL ;
    SHAPE ABUTMENT ;
    PORT
      LAYER M4 ;
      RECT 0.000 8.112 0.024 8.136 ;
    END
  END rw0_rd_out[12]
  PIN rw0_rd_out[13]
    DIRECTION OUTPUT ;
    USE SIGNAL ;
    SHAPE ABUTMENT ;
    PORT
      LAYER M4 ;
      RECT 0.000 8.208 0.024 8.232 ;
    END
  END rw0_rd_out[13]
  PIN rw0_rd_out[14]
    DIRECTION OUTPUT ;
    USE SIGNAL ;
    SHAPE ABUTMENT ;
    PORT
      LAYER M4 ;
      RECT 0.000 8.304 0.024 8.328 ;
    END
  END rw0_rd_out[14]
  PIN rw0_rd_out[15]
    DIRECTION OUTPUT ;
    USE SIGNAL ;
    SHAPE ABUTMENT ;
    PORT
      LAYER M4 ;
      RECT 0.000 8.400 0.024 8.424 ;
    END
  END rw0_rd_out[15]
  PIN rw0_rd_out[16]
    DIRECTION OUTPUT ;
    USE SIGNAL ;
    SHAPE ABUTMENT ;
    PORT
      LAYER M4 ;
      RECT 0.000 8.496 0.024 8.520 ;
    END
  END rw0_rd_out[16]
  PIN rw0_rd_out[17]
    DIRECTION OUTPUT ;
    USE SIGNAL ;
    SHAPE ABUTMENT ;
    PORT
      LAYER M4 ;
      RECT 0.000 8.592 0.024 8.616 ;
    END
  END rw0_rd_out[17]
  PIN rw0_rd_out[18]
    DIRECTION OUTPUT ;
    USE SIGNAL ;
    SHAPE ABUTMENT ;
    PORT
      LAYER M4 ;
      RECT 0.000 8.688 0.024 8.712 ;
    END
  END rw0_rd_out[18]
  PIN rw0_rd_out[19]
    DIRECTION OUTPUT ;
    USE SIGNAL ;
    SHAPE ABUTMENT ;
    PORT
      LAYER M4 ;
      RECT 0.000 8.784 0.024 8.808 ;
    END
  END rw0_rd_out[19]
  PIN rw0_rd_out[20]
    DIRECTION OUTPUT ;
    USE SIGNAL ;
    SHAPE ABUTMENT ;
    PORT
      LAYER M4 ;
      RECT 0.000 8.880 0.024 8.904 ;
    END
  END rw0_rd_out[20]
  PIN rw0_rd_out[21]
    DIRECTION OUTPUT ;
    USE SIGNAL ;
    SHAPE ABUTMENT ;
    PORT
      LAYER M4 ;
      RECT 0.000 8.976 0.024 9.000 ;
    END
  END rw0_rd_out[21]
  PIN rw0_rd_out[22]
    DIRECTION OUTPUT ;
    USE SIGNAL ;
    SHAPE ABUTMENT ;
    PORT
      LAYER M4 ;
      RECT 0.000 9.072 0.024 9.096 ;
    END
  END rw0_rd_out[22]
  PIN rw0_rd_out[23]
    DIRECTION OUTPUT ;
    USE SIGNAL ;
    SHAPE ABUTMENT ;
    PORT
      LAYER M4 ;
      RECT 0.000 9.168 0.024 9.192 ;
    END
  END rw0_rd_out[23]
  PIN rw0_rd_out[24]
    DIRECTION OUTPUT ;
    USE SIGNAL ;
    SHAPE ABUTMENT ;
    PORT
      LAYER M4 ;
      RECT 0.000 9.264 0.024 9.288 ;
    END
  END rw0_rd_out[24]
  PIN rw0_rd_out[25]
    DIRECTION OUTPUT ;
    USE SIGNAL ;
    SHAPE ABUTMENT ;
    PORT
      LAYER M4 ;
      RECT 0.000 9.360 0.024 9.384 ;
    END
  END rw0_rd_out[25]
  PIN rw0_rd_out[26]
    DIRECTION OUTPUT ;
    USE SIGNAL ;
    SHAPE ABUTMENT ;
    PORT
      LAYER M4 ;
      RECT 0.000 9.456 0.024 9.480 ;
    END
  END rw0_rd_out[26]
  PIN rw0_rd_out[27]
    DIRECTION OUTPUT ;
    USE SIGNAL ;
    SHAPE ABUTMENT ;
    PORT
      LAYER M4 ;
      RECT 0.000 9.552 0.024 9.576 ;
    END
  END rw0_rd_out[27]
  PIN rw0_rd_out[28]
    DIRECTION OUTPUT ;
    USE SIGNAL ;
    SHAPE ABUTMENT ;
    PORT
      LAYER M4 ;
      RECT 0.000 9.648 0.024 9.672 ;
    END
  END rw0_rd_out[28]
  PIN rw0_rd_out[29]
    DIRECTION OUTPUT ;
    USE SIGNAL ;
    SHAPE ABUTMENT ;
    PORT
      LAYER M4 ;
      RECT 0.000 9.744 0.024 9.768 ;
    END
  END rw0_rd_out[29]
  PIN rw0_rd_out[30]
    DIRECTION OUTPUT ;
    USE SIGNAL ;
    SHAPE ABUTMENT ;
    PORT
      LAYER M4 ;
      RECT 0.000 9.840 0.024 9.864 ;
    END
  END rw0_rd_out[30]
  PIN rw0_rd_out[31]
    DIRECTION OUTPUT ;
    USE SIGNAL ;
    SHAPE ABUTMENT ;
    PORT
      LAYER M4 ;
      RECT 0.000 9.936 0.024 9.960 ;
    END
  END rw0_rd_out[31]
  PIN rw0_rd_out[32]
    DIRECTION OUTPUT ;
    USE SIGNAL ;
    SHAPE ABUTMENT ;
    PORT
      LAYER M4 ;
      RECT 0.000 10.032 0.024 10.056 ;
    END
  END rw0_rd_out[32]
  PIN rw0_rd_out[33]
    DIRECTION OUTPUT ;
    USE SIGNAL ;
    SHAPE ABUTMENT ;
    PORT
      LAYER M4 ;
      RECT 0.000 10.128 0.024 10.152 ;
    END
  END rw0_rd_out[33]
  PIN rw0_rd_out[34]
    DIRECTION OUTPUT ;
    USE SIGNAL ;
    SHAPE ABUTMENT ;
    PORT
      LAYER M4 ;
      RECT 0.000 10.224 0.024 10.248 ;
    END
  END rw0_rd_out[34]
  PIN rw0_rd_out[35]
    DIRECTION OUTPUT ;
    USE SIGNAL ;
    SHAPE ABUTMENT ;
    PORT
      LAYER M4 ;
      RECT 0.000 10.320 0.024 10.344 ;
    END
  END rw0_rd_out[35]
  PIN rw0_rd_out[36]
    DIRECTION OUTPUT ;
    USE SIGNAL ;
    SHAPE ABUTMENT ;
    PORT
      LAYER M4 ;
      RECT 0.000 10.416 0.024 10.440 ;
    END
  END rw0_rd_out[36]
  PIN rw0_rd_out[37]
    DIRECTION OUTPUT ;
    USE SIGNAL ;
    SHAPE ABUTMENT ;
    PORT
      LAYER M4 ;
      RECT 0.000 10.512 0.024 10.536 ;
    END
  END rw0_rd_out[37]
  PIN rw0_rd_out[38]
    DIRECTION OUTPUT ;
    USE SIGNAL ;
    SHAPE ABUTMENT ;
    PORT
      LAYER M4 ;
      RECT 0.000 10.608 0.024 10.632 ;
    END
  END rw0_rd_out[38]
  PIN rw0_rd_out[39]
    DIRECTION OUTPUT ;
    USE SIGNAL ;
    SHAPE ABUTMENT ;
    PORT
      LAYER M4 ;
      RECT 0.000 10.704 0.024 10.728 ;
    END
  END rw0_rd_out[39]
  PIN rw0_rd_out[40]
    DIRECTION OUTPUT ;
    USE SIGNAL ;
    SHAPE ABUTMENT ;
    PORT
      LAYER M4 ;
      RECT 0.000 10.800 0.024 10.824 ;
    END
  END rw0_rd_out[40]
  PIN rw0_rd_out[41]
    DIRECTION OUTPUT ;
    USE SIGNAL ;
    SHAPE ABUTMENT ;
    PORT
      LAYER M4 ;
      RECT 0.000 10.896 0.024 10.920 ;
    END
  END rw0_rd_out[41]
  PIN rw0_rd_out[42]
    DIRECTION OUTPUT ;
    USE SIGNAL ;
    SHAPE ABUTMENT ;
    PORT
      LAYER M4 ;
      RECT 0.000 10.992 0.024 11.016 ;
    END
  END rw0_rd_out[42]
  PIN rw0_rd_out[43]
    DIRECTION OUTPUT ;
    USE SIGNAL ;
    SHAPE ABUTMENT ;
    PORT
      LAYER M4 ;
      RECT 0.000 11.088 0.024 11.112 ;
    END
  END rw0_rd_out[43]
  PIN rw0_rd_out[44]
    DIRECTION OUTPUT ;
    USE SIGNAL ;
    SHAPE ABUTMENT ;
    PORT
      LAYER M4 ;
      RECT 0.000 11.184 0.024 11.208 ;
    END
  END rw0_rd_out[44]
  PIN rw0_rd_out[45]
    DIRECTION OUTPUT ;
    USE SIGNAL ;
    SHAPE ABUTMENT ;
    PORT
      LAYER M4 ;
      RECT 0.000 11.280 0.024 11.304 ;
    END
  END rw0_rd_out[45]
  PIN rw0_rd_out[46]
    DIRECTION OUTPUT ;
    USE SIGNAL ;
    SHAPE ABUTMENT ;
    PORT
      LAYER M4 ;
      RECT 0.000 11.376 0.024 11.400 ;
    END
  END rw0_rd_out[46]
  PIN rw0_rd_out[47]
    DIRECTION OUTPUT ;
    USE SIGNAL ;
    SHAPE ABUTMENT ;
    PORT
      LAYER M4 ;
      RECT 0.000 11.472 0.024 11.496 ;
    END
  END rw0_rd_out[47]
  PIN rw0_rd_out[48]
    DIRECTION OUTPUT ;
    USE SIGNAL ;
    SHAPE ABUTMENT ;
    PORT
      LAYER M4 ;
      RECT 0.000 11.568 0.024 11.592 ;
    END
  END rw0_rd_out[48]
  PIN rw0_rd_out[49]
    DIRECTION OUTPUT ;
    USE SIGNAL ;
    SHAPE ABUTMENT ;
    PORT
      LAYER M4 ;
      RECT 0.000 11.664 0.024 11.688 ;
    END
  END rw0_rd_out[49]
  PIN rw0_rd_out[50]
    DIRECTION OUTPUT ;
    USE SIGNAL ;
    SHAPE ABUTMENT ;
    PORT
      LAYER M4 ;
      RECT 0.000 11.760 0.024 11.784 ;
    END
  END rw0_rd_out[50]
  PIN rw0_rd_out[51]
    DIRECTION OUTPUT ;
    USE SIGNAL ;
    SHAPE ABUTMENT ;
    PORT
      LAYER M4 ;
      RECT 0.000 11.856 0.024 11.880 ;
    END
  END rw0_rd_out[51]
  PIN rw0_rd_out[52]
    DIRECTION OUTPUT ;
    USE SIGNAL ;
    SHAPE ABUTMENT ;
    PORT
      LAYER M4 ;
      RECT 0.000 11.952 0.024 11.976 ;
    END
  END rw0_rd_out[52]
  PIN rw0_rd_out[53]
    DIRECTION OUTPUT ;
    USE SIGNAL ;
    SHAPE ABUTMENT ;
    PORT
      LAYER M4 ;
      RECT 0.000 12.048 0.024 12.072 ;
    END
  END rw0_rd_out[53]
  PIN rw0_rd_out[54]
    DIRECTION OUTPUT ;
    USE SIGNAL ;
    SHAPE ABUTMENT ;
    PORT
      LAYER M4 ;
      RECT 0.000 12.144 0.024 12.168 ;
    END
  END rw0_rd_out[54]
  PIN rw0_rd_out[55]
    DIRECTION OUTPUT ;
    USE SIGNAL ;
    SHAPE ABUTMENT ;
    PORT
      LAYER M4 ;
      RECT 0.000 12.240 0.024 12.264 ;
    END
  END rw0_rd_out[55]
  PIN rw0_rd_out[56]
    DIRECTION OUTPUT ;
    USE SIGNAL ;
    SHAPE ABUTMENT ;
    PORT
      LAYER M4 ;
      RECT 0.000 12.336 0.024 12.360 ;
    END
  END rw0_rd_out[56]
  PIN rw0_rd_out[57]
    DIRECTION OUTPUT ;
    USE SIGNAL ;
    SHAPE ABUTMENT ;
    PORT
      LAYER M4 ;
      RECT 0.000 12.432 0.024 12.456 ;
    END
  END rw0_rd_out[57]
  PIN rw0_rd_out[58]
    DIRECTION OUTPUT ;
    USE SIGNAL ;
    SHAPE ABUTMENT ;
    PORT
      LAYER M4 ;
      RECT 0.000 12.528 0.024 12.552 ;
    END
  END rw0_rd_out[58]
  PIN rw0_rd_out[59]
    DIRECTION OUTPUT ;
    USE SIGNAL ;
    SHAPE ABUTMENT ;
    PORT
      LAYER M4 ;
      RECT 0.000 12.624 0.024 12.648 ;
    END
  END rw0_rd_out[59]
  PIN rw0_rd_out[60]
    DIRECTION OUTPUT ;
    USE SIGNAL ;
    SHAPE ABUTMENT ;
    PORT
      LAYER M4 ;
      RECT 0.000 12.720 0.024 12.744 ;
    END
  END rw0_rd_out[60]
  PIN rw0_rd_out[61]
    DIRECTION OUTPUT ;
    USE SIGNAL ;
    SHAPE ABUTMENT ;
    PORT
      LAYER M4 ;
      RECT 0.000 12.816 0.024 12.840 ;
    END
  END rw0_rd_out[61]
  PIN rw0_rd_out[62]
    DIRECTION OUTPUT ;
    USE SIGNAL ;
    SHAPE ABUTMENT ;
    PORT
      LAYER M4 ;
      RECT 0.000 12.912 0.024 12.936 ;
    END
  END rw0_rd_out[62]
  PIN rw0_rd_out[63]
    DIRECTION OUTPUT ;
    USE SIGNAL ;
    SHAPE ABUTMENT ;
    PORT
      LAYER M4 ;
      RECT 0.000 13.008 0.024 13.032 ;
    END
  END rw0_rd_out[63]
  PIN rw0_we_in
    DIRECTION INPUT ;
    USE SIGNAL ;
    SHAPE ABUTMENT ;
    PORT
      LAYER M4 ;
      RECT 0.000 13.200 0.024 13.224 ;
    END
  END rw0_we_in
  PIN rw0_ce_in
    DIRECTION INPUT ;
    USE SIGNAL ;
    SHAPE ABUTMENT ;
    PORT
      LAYER M4 ;
      RECT 0.000 13.296 0.024 13.320 ;
    END
  END rw0_ce_in
  PIN rw0_clk
    DIRECTION INPUT ;
    USE SIGNAL ;
    SHAPE ABUTMENT ;
    PORT
      LAYER M4 ;
      RECT 0.000 13.392 0.024 13.416 ;
    END
  END rw0_clk
  PIN VSS
    DIRECTION INOUT ;
    USE GROUND ;
    PORT
      LAYER M4 ;
      RECT 0.048 0.000 24.836 0.096 ;
      RECT 0.048 0.768 24.836 0.864 ;
      RECT 0.048 1.536 24.836 1.632 ;
      RECT 0.048 2.304 24.836 2.400 ;
      RECT 0.048 3.072 24.836 3.168 ;
      RECT 0.048 3.840 24.836 3.936 ;
      RECT 0.048 4.608 24.836 4.704 ;
      RECT 0.048 5.376 24.836 5.472 ;
      RECT 0.048 6.144 24.836 6.240 ;
      RECT 0.048 6.912 24.836 7.008 ;
      RECT 0.048 7.680 24.836 7.776 ;
      RECT 0.048 8.448 24.836 8.544 ;
      RECT 0.048 9.216 24.836 9.312 ;
      RECT 0.048 9.984 24.836 10.080 ;
      RECT 0.048 10.752 24.836 10.848 ;
      RECT 0.048 11.520 24.836 11.616 ;
      RECT 0.048 12.288 24.836 12.384 ;
      RECT 0.048 13.056 24.836 13.152 ;
    END
  END VSS
  PIN VDD
    DIRECTION INOUT ;
    USE POWER ;
    PORT
      LAYER M4 ;
      RECT 0.048 0.384 24.836 0.480 ;
      RECT 0.048 1.152 24.836 1.248 ;
      RECT 0.048 1.920 24.836 2.016 ;
      RECT 0.048 2.688 24.836 2.784 ;
      RECT 0.048 3.456 24.836 3.552 ;
      RECT 0.048 4.224 24.836 4.320 ;
      RECT 0.048 4.992 24.836 5.088 ;
      RECT 0.048 5.760 24.836 5.856 ;
      RECT 0.048 6.528 24.836 6.624 ;
      RECT 0.048 7.296 24.836 7.392 ;
      RECT 0.048 8.064 24.836 8.160 ;
      RECT 0.048 8.832 24.836 8.928 ;
      RECT 0.048 9.600 24.836 9.696 ;
      RECT 0.048 10.368 24.836 10.464 ;
      RECT 0.048 11.136 24.836 11.232 ;
      RECT 0.048 11.904 24.836 12.000 ;
      RECT 0.048 12.672 24.836 12.768 ;
    END
  END VDD
  OBS
    LAYER M1 ;
    RECT 0 0 24.884 13.479 ;
    LAYER M2 ;
    RECT 0 0 24.884 13.479 ;
    LAYER M3 ;
    RECT 0 0 24.884 13.479 ;
    LAYER M4 ;
    RECT 0 0 24.884 13.479 ;
  END
END liteeth_1rw1r_64w64d_sram

END LIBRARY
